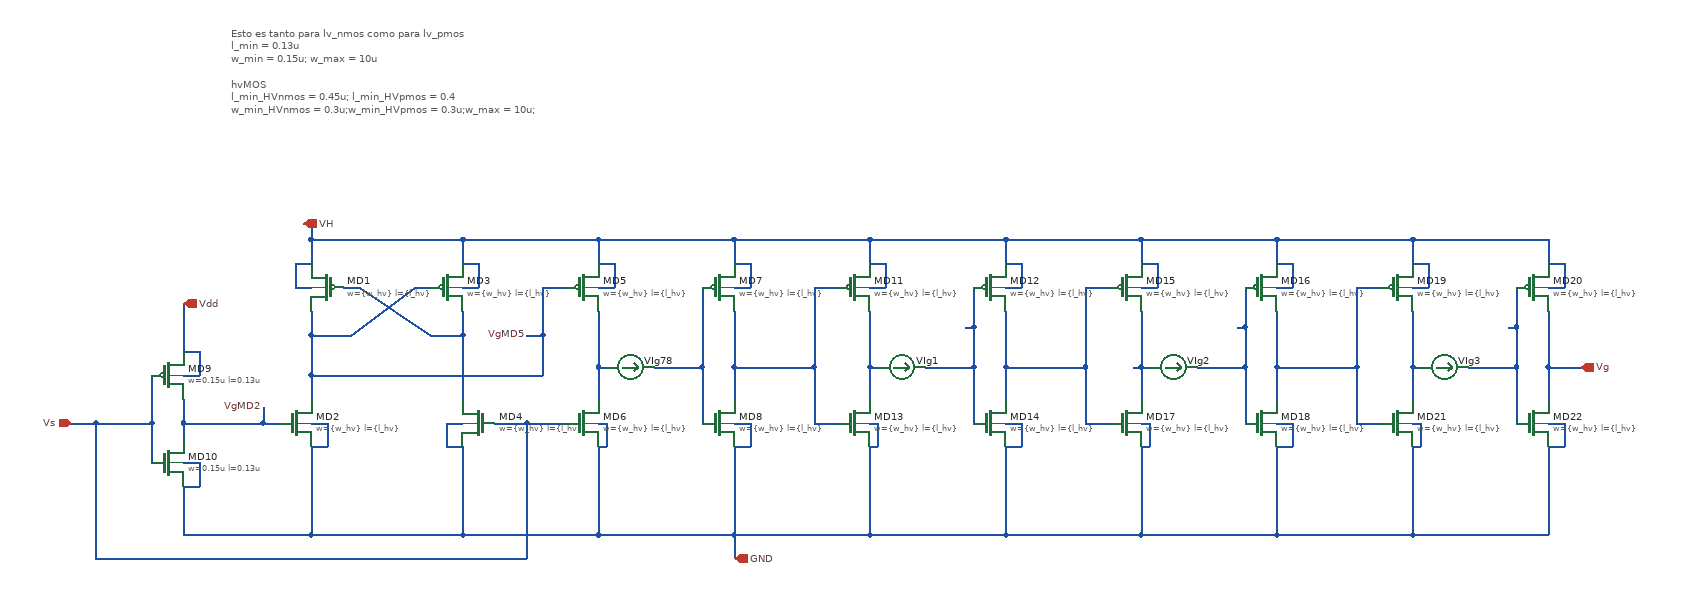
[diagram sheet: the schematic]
v {xschem version=3.4.5 file_version=1.2
}
G {}
K {}
V {}
S {}
E {}
T {Esto es tanto para lv_nmos como para lv_pmos
l_min = 0.13u
w_min = 0.15u; w_max = 10u

hvMOS
l_min_HVnmos = 0.45u; l_min_HVpmos = 0.4
w_min_HVnmos = 0.3u;w_min_HVpmos = 0.3u;w_max = 10u;
} -580 -330 0 0 0.4 0.4 {}
N -640 250 -640 310 {
lab=GND}
N -640 170 -640 190 {
lab=VgMD2}
N -640 140 -640 170 {
lab=VgMD2}
N -480 110 -480 140 {
lab=VgMD5}
N -540 170 -520 170 {
lab=VgMD2}
N -440 0 -420 0 {
lab=#net1}
N -120 100 -120 140 {
lab=#net2}
N -290 60 -290 140 {
lab=#net1}
N -420 0 -330 60 {
lab=#net1}
N -330 60 -290 60 {
lab=#net1}
N -290 30 -290 60 {
lab=#net1}
N -480 60 -430 60 {
lab=VgMD5}
N -480 30 -480 60 {
lab=VgMD5}
N -350 0 -330 0 {
lab=VgMD5}
N -430 60 -350 0 {
lab=VgMD5}
N -480 110 -190 110 {
lab=VgMD5}
N -480 60 -480 110 {
lab=VgMD5}
N -190 60 -190 110 {
lab=VgMD5}
N -190 0 -160 0 {
lab=VgMD5}
N -210 170 -160 170 {
lab=Vs}
N -210 170 -210 340 {
lab=Vs}
N -250 170 -210 170 {
lab=Vs}
N -750 340 -210 340 {
lab=Vs}
N -750 170 -750 340 {
lab=Vs}
N -120 310 50 310 {
lab=GND}
N 50 200 50 310 {
lab=GND}
N -120 200 -120 310 {
lab=GND}
N -290 310 -120 310 {
lab=GND}
N -290 200 -290 310 {
lab=GND}
N -480 310 -290 310 {
lab=GND}
N -480 200 -480 310 {
lab=GND}
N -640 310 -480 310 {
lab=GND}
N -680 170 -680 220 {
lab=Vs}
N -750 170 -680 170 {
lab=Vs}
N -680 110 -680 170 {
lab=Vs}
N 10 100 10 170 {
lab=#net3}
N -120 30 -120 100 {
lab=#net2}
N 50 100 50 140 {
lab=#net4}
N -480 -60 -480 -30 {
lab=VH}
N -120 -60 50 -60 {
lab=VH}
N 50 -60 50 -30 {
lab=VH}
N -120 -60 -120 -30 {
lab=VH}
N -290 -60 -120 -60 {
lab=VH}
N -290 -60 -290 -30 {
lab=VH}
N -480 -60 -290 -60 {
lab=VH}
N -480 -80 -480 -60 {
lab=VH}
N -490 -80 -480 -80 {
lab=VH}
N -640 20 -640 80 {
lab=Vdd}
N -780 170 -750 170 {
lab=Vs}
N 50 310 50 340 {
lab=GND}
N 50 100 150 100 {
lab=#net4}
N 50 30 50 100 {
lab=#net4}
N -480 170 -460 170 {
lab=GND}
N -460 170 -460 200 {
lab=GND}
N -480 200 -460 200 {
lab=GND}
N -310 170 -290 170 {
lab=GND}
N -310 170 -310 200 {
lab=GND}
N -310 200 -290 200 {
lab=GND}
N -120 170 -110 170 {
lab=GND}
N -110 170 -110 200 {
lab=GND}
N -120 200 -110 200 {
lab=GND}
N 50 170 70 170 {
lab=GND}
N 70 170 70 200 {
lab=GND}
N 50 200 70 200 {
lab=GND}
N -500 0 -480 0 {
lab=VH}
N -500 -30 -500 0 {
lab=VH}
N -500 -30 -480 -30 {
lab=VH}
N -290 0 -270 0 {
lab=VH}
N -270 -30 -270 0 {
lab=VH}
N -290 -30 -270 -30 {
lab=VH}
N -120 0 -100 0 {
lab=VH}
N -100 -30 -100 0 {
lab=VH}
N -120 -30 -100 -30 {
lab=VH}
N 50 0 70 0 {
lab=VH}
N 70 -30 70 0 {
lab=VH}
N 50 -30 70 -30 {
lab=VH}
N -640 110 -620 110 {
lab=Vdd}
N -620 80 -620 110 {
lab=Vdd}
N -640 80 -620 80 {
lab=Vdd}
N -640 220 -620 220 {
lab=GND}
N -620 220 -620 250 {
lab=GND}
N -640 250 -620 250 {
lab=GND}
N -540 150 -540 170 {
lab=VgMD2}
N -640 170 -540 170 {
lab=VgMD2}
N -210 60 -190 60 {
lab=VgMD5}
N -190 0 -190 60 {
lab=VgMD5}
N -50 100 10 100 {
lab=#net3}
N -120 100 -110 100 {
lab=#net2}
N 10 0 10 100 {
lab=#net3}
N 220 100 220 140 {
lab=#net5}
N 150 0 180 0 {
lab=#net4}
N 150 170 180 170 {
lab=#net4}
N 220 310 390 310 {
lab=GND}
N 390 200 390 310 {
lab=GND}
N 220 200 220 310 {
lab=GND}
N 50 310 220 310 {
lab=GND}
N 350 100 350 170 {
lab=#net6}
N 220 30 220 100 {
lab=#net5}
N 350 50 350 100 {
lab=#net6}
N 390 100 390 140 {
lab=#net7}
N 220 -60 390 -60 {
lab=VH}
N 390 -60 390 -30 {
lab=VH}
N 220 -60 220 -30 {
lab=VH}
N 50 -60 220 -60 {
lab=VH}
N 390 100 490 100 {
lab=#net7}
N 390 30 390 100 {
lab=#net7}
N 220 170 230 170 {
lab=GND}
N 230 170 230 200 {
lab=GND}
N 220 200 230 200 {
lab=GND}
N 390 170 410 170 {
lab=GND}
N 410 170 410 200 {
lab=GND}
N 390 200 410 200 {
lab=GND}
N 220 0 240 0 {
lab=VH}
N 240 -30 240 0 {
lab=VH}
N 220 -30 240 -30 {
lab=VH}
N 390 0 410 0 {
lab=VH}
N 410 -30 410 0 {
lab=VH}
N 390 -30 410 -30 {
lab=VH}
N 290 100 350 100 {
lab=#net6}
N 220 100 230 100 {
lab=#net5}
N 340 50 350 50 {
lab=#net6}
N 350 0 350 50 {
lab=#net6}
N 560 100 560 140 {
lab=#net8}
N 490 0 520 0 {
lab=#net7}
N 490 170 520 170 {
lab=#net7}
N 560 310 730 310 {
lab=GND}
N 730 200 730 310 {
lab=GND}
N 560 200 560 310 {
lab=GND}
N 390 310 560 310 {
lab=GND}
N 690 100 690 170 {
lab=#net9}
N 560 30 560 100 {
lab=#net8}
N 690 50 690 100 {
lab=#net9}
N 730 100 730 140 {
lab=#net10}
N 560 -60 730 -60 {
lab=VH}
N 730 -60 730 -30 {
lab=VH}
N 560 -60 560 -30 {
lab=VH}
N 390 -60 560 -60 {
lab=VH}
N 730 100 830 100 {
lab=#net10}
N 730 30 730 100 {
lab=#net10}
N 560 170 570 170 {
lab=GND}
N 570 170 570 200 {
lab=GND}
N 560 200 570 200 {
lab=GND}
N 730 170 750 170 {
lab=GND}
N 750 170 750 200 {
lab=GND}
N 730 200 750 200 {
lab=GND}
N 560 0 580 0 {
lab=VH}
N 580 -30 580 0 {
lab=VH}
N 560 -30 580 -30 {
lab=VH}
N 730 0 750 0 {
lab=VH}
N 750 -30 750 0 {
lab=VH}
N 730 -30 750 -30 {
lab=VH}
N 550 100 560 100 {
lab=#net8}
N 630 100 690 100 {
lab=#net9}
N 560 100 570 100 {
lab=#net8}
N 680 50 690 50 {
lab=#net9}
N 690 0 690 50 {
lab=#net9}
N 900 100 900 140 {
lab=#net11}
N 830 0 860 0 {
lab=#net10}
N 830 170 860 170 {
lab=#net10}
N 900 310 1070 310 {
lab=GND}
N 1070 200 1070 310 {
lab=GND}
N 900 200 900 310 {
lab=GND}
N 730 310 900 310 {
lab=GND}
N 1030 100 1030 170 {
lab=#net12}
N 900 30 900 100 {
lab=#net11}
N 1030 50 1030 100 {
lab=#net12}
N 1070 100 1070 140 {
lab=Vg}
N 900 -60 1070 -60 {
lab=VH}
N 1070 -60 1070 -30 {
lab=VH}
N 900 -60 900 -30 {
lab=VH}
N 730 -60 900 -60 {
lab=VH}
N 1070 100 1110 100 {
lab=Vg}
N 1070 30 1070 100 {
lab=Vg}
N 900 170 910 170 {
lab=GND}
N 910 170 910 200 {
lab=GND}
N 900 200 910 200 {
lab=GND}
N 1070 170 1090 170 {
lab=GND}
N 1090 170 1090 200 {
lab=GND}
N 1070 200 1090 200 {
lab=GND}
N 900 0 920 0 {
lab=VH}
N 920 -30 920 0 {
lab=VH}
N 900 -30 920 -30 {
lab=VH}
N 1070 0 1090 0 {
lab=VH}
N 1090 -30 1090 0 {
lab=VH}
N 1070 -30 1090 -30 {
lab=VH}
N 970 100 1030 100 {
lab=#net12}
N 900 100 910 100 {
lab=#net11}
N 1020 50 1030 50 {
lab=#net12}
N 1030 0 1030 50 {
lab=#net12}
N 150 100 150 170 {
lab=#net4}
N 150 0 150 100 {
lab=#net4}
N 490 100 490 170 {
lab=#net7}
N 490 0 490 100 {
lab=#net7}
N 830 100 830 170 {
lab=#net10}
N 830 0 830 100 {
lab=#net10}
C {sg13g2_pr/sg13_lv_pmos.sym} -660 110 0 0 {name=MD9
l=0.13u
w=0.15u
ng=1
m=3
model=sg13_lv_pmos
spiceprefix=X
}
C {sg13g2_pr/sg13_lv_nmos.sym} -660 220 2 1 {name=MD10
l = 0.13u
w = 0.15u
ng= 1
m= 1
model=sg13_lv_nmos
spiceprefix=X
}
C {sg13g2_pr/sg13_hv_pmos.sym} -460 0 0 1 {name=MD1
l=\{l_hv\}
w=\{w_hv\}
ng= 1
m= 1
model=sg13_hv_pmos
spiceprefix=X
}
C {sg13g2_pr/sg13_hv_nmos.sym} -500 170 2 1 {name=MD2
l = \{l_hv\}
w = \{w_hv\}
ng= 1
m= 3
model=sg13_hv_nmos
spiceprefix=X
}
C {sg13g2_pr/sg13_hv_nmos.sym} -140 170 2 1 {name=MD6
l=\{l_hv\}
w=\{w_hv\}
ng= 1
m=\{mult1_GD2\}
model=sg13_hv_nmos
spiceprefix=X
}
C {iopin.sym} -490 -80 0 1 {name=p1 lab=VH}
C {iopin.sym} -640 20 0 1 {name=p2 lab=Vdd}
C {ipin.sym} -780 170 0 0 {name=p3 lab=Vs}
C {iopin.sym} 50 340 0 1 {name=p5 lab=GND}
C {lab_pin.sym} -540 150 0 0 {name=p6 sig_type=std_logic lab=VgMD2}
C {lab_pin.sym} -210 60 0 0 {name=p7 sig_type=std_logic lab=VgMD5}
C {ammeter.sym} -80 100 3 0 {name=VIg78 savecurrent=true spice_ignore=0}
C {ammeter.sym} 260 100 3 0 {name=VIg1 savecurrent=true spice_ignore=0}
C {ammeter.sym} 600 100 3 0 {name=VIg2 savecurrent=true spice_ignore=0}
C {opin.sym} 1110 100 0 0 {name=p13 lab=Vg}
C {ammeter.sym} 940 100 3 0 {name=VIg3 savecurrent=true spice_ignore=0}
C {sg13g2_pr/sg13_hv_pmos.sym} -310 0 0 0 {name=MD3
l=\{l_hv\}
w=\{w_hv\}
ng= 1
m= 1
model=sg13_hv_pmos
spiceprefix=X
}
C {sg13g2_pr/sg13_hv_nmos.sym} -270 170 2 0 {name=MD4
l = \{l_hv\}
w = \{w_hv\}
ng= 1
m= 3
model=sg13_hv_nmos
spiceprefix=X
}
C {sg13g2_pr/sg13_hv_pmos.sym} -140 0 0 0 {name=MD5
l=\{l_hv\}
w=\{w_hv\}
ng= 1
m= \{3*mult1_GD2\}
model=sg13_hv_pmos
spiceprefix=X
}
C {sg13g2_pr/sg13_hv_pmos.sym} 30 0 0 0 {name=MD7
l=\{l_hv\}
w=\{w_hv\}
ng= 1
m= \{3*mult2_GD2\}
model=sg13_hv_pmos
spiceprefix=X
}
C {sg13g2_pr/sg13_hv_pmos.sym} 200 0 0 0 {name=MD11
l=\{l_hv\}
w=\{w_hv\}
ng= 1
m= \{3*mult3_GD2\}
model=sg13_hv_pmos
spiceprefix=X
}
C {sg13g2_pr/sg13_hv_pmos.sym} 370 0 0 0 {name=MD12
l=\{l_hv\}
w=\{w_hv\}
ng= 1
m= \{3*mult4_GD2\}
model=sg13_hv_pmos
spiceprefix=X
}
C {sg13g2_pr/sg13_hv_pmos.sym} 540 0 0 0 {name=MD15
l=\{l_hv\}
w=\{w_hv\}
ng= 1
m= \{3*mult5_GD2\}
model=sg13_hv_pmos
spiceprefix=X
}
C {sg13g2_pr/sg13_hv_pmos.sym} 710 0 0 0 {name=MD16
l=\{l_hv\}
w=\{w_hv\}
ng= 1
m= \{3*mult6_GD2\}
model=sg13_hv_pmos
spiceprefix=X
}
C {sg13g2_pr/sg13_hv_pmos.sym} 880 0 0 0 {name=MD19
l=\{l_hv\}
w=\{w_hv\}
ng= 1
m= \{3*mult7_GD2\}
model=sg13_hv_pmos
spiceprefix=X
}
C {sg13g2_pr/sg13_hv_pmos.sym} 1050 0 0 0 {name=MD20
l=\{l_hv\}
w=\{w_hv\}
ng= 1
m= \{3*mult8_GD2\}
model=sg13_hv_pmos
spiceprefix=X
}
C {sg13g2_pr/sg13_hv_nmos.sym} 30 170 2 1 {name=MD8
l=\{l_hv\}
w=\{w_hv\}
ng= 1
m=\{mult2_GD2\}
model=sg13_hv_nmos
spiceprefix=X
}
C {sg13g2_pr/sg13_hv_nmos.sym} 200 170 2 1 {name=MD13
l=\{l_hv\}
w=\{w_hv\}
ng= 1
m=\{mult3_GD2\}
model=sg13_hv_nmos
spiceprefix=X
}
C {sg13g2_pr/sg13_hv_nmos.sym} 370 170 2 1 {name=MD14
l=\{l_hv\}
w=\{w_hv\}
ng= 1
m=\{mult4_GD2\}
model=sg13_hv_nmos
spiceprefix=X
}
C {sg13g2_pr/sg13_hv_nmos.sym} 540 170 2 1 {name=MD17
l=\{l_hv\}
w=\{w_hv\}
ng= 1
m=\{mult5_GD2\}
model=sg13_hv_nmos
spiceprefix=X
}
C {sg13g2_pr/sg13_hv_nmos.sym} 710 170 2 1 {name=MD18
l=\{l_hv\}
w=\{w_hv\}
ng= 1
m=\{mult6_GD2\}
model=sg13_hv_nmos
spiceprefix=X
}
C {sg13g2_pr/sg13_hv_nmos.sym} 880 170 2 1 {name=MD21
l=\{l_hv\}
w=\{w_hv\}
ng= 1
m=\{mult7_GD2\}
model=sg13_hv_nmos
spiceprefix=X
}
C {sg13g2_pr/sg13_hv_nmos.sym} 1050 170 2 1 {name=MD22
l=\{l_hv\}
w=\{w_hv\}
ng= 1
m=\{mult8_GD2\}
model=sg13_hv_nmos
spiceprefix=X
}
